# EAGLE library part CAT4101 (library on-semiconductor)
1A Constant-Current LED Driver with PWM Dimming Source: ON Semiconductor .. 4101.pdf

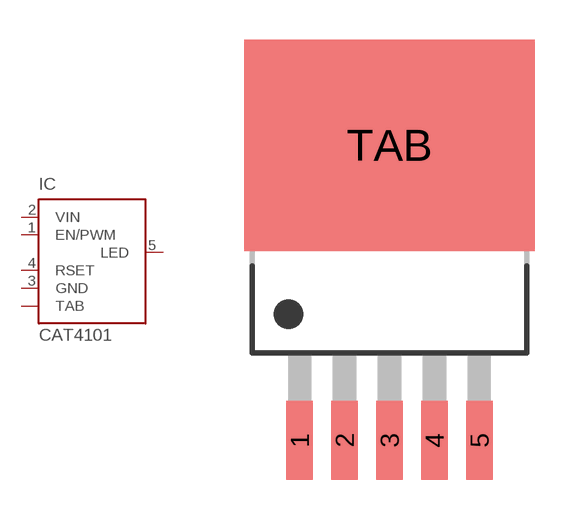
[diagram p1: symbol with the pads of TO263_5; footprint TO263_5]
Designator prefix IC

## CAT4101 (MPN: CAT4101TV-T75; OC_FARNELL: 1718452; OC_NEWARK: 08R5264)  [TO263_5]
1  EN/PWM  in
2  VIN  in
3  GND  pwr
4  RSET  in
5  LED  pwr
TAB  TAB  pas

## Footprint TO263_5 (pad centres in mm)
TO-263 5-LEAD (TV) Source: ON Semiconductor .. 4101.pdf
smd 1 x 3: 1 -3.4,-8; 2 -1.7,-8; 3 0,-8; 4 1.7,-8; 5 3.4,-8
smd 11 x 8: TAB 0,3.175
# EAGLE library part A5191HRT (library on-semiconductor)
HART Modem Single-chip, half-duplex 1200 bits per second FSK modem Auto generated by make-symbol-device-package-bsdl.ulp Rev. 35 Source:OnSemi A5191HRT HART Modem Data Sheet.pdf

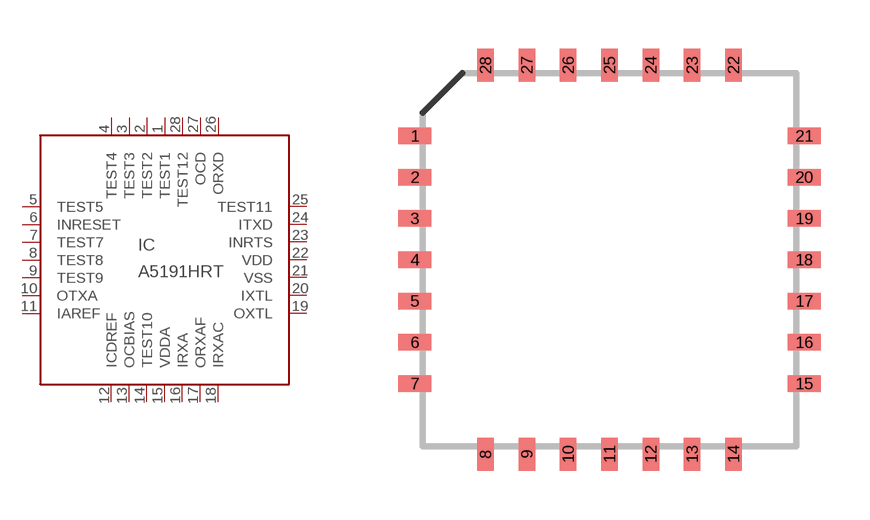
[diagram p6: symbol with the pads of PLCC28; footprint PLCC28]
Designator prefix IC

## A5191HRT (MPN: A5191HRTPG-XTD; OC_FARNELL: unknown; OC_NEWARK: 03P1167)  [PLCC28]
1  TEST1  in
2  TEST2  nc
3  TEST3  nc
4  TEST4  nc
5  TEST5  in
6  INRESET  in
7  TEST7  in
8  TEST8  in
9  TEST9  in
10  OTXA  out
11  IAREF  in
12  ICDREF  in
13  OCBIAS  out
14  TEST10  in
15  VDDA  pwr
16  IRXA  in
17  ORXAF  out
18  IRXAC  in
19  OXTL  out
20  IXTL  in
21  VSS  pwr
22  VDD  pwr
23  INRTS  in
24  ITXD  in
25  TEST11  nc
26  ORXD  out
27  OCD  out
28  TEST12  nc

## Footprint PLCC28 (pad centres in mm)
Auto generated by make-symbol-device-package-bsdl.ulp Rev. 35
smd 1.016 x 0.508: 1 -5.982,3.81; 2 -5.982,2.54; 3 -5.982,1.27; 4 -5.982,0; 5 -5.982,-1.27; 6 -5.982,-2.54; 7 -5.982,-3.81; 15 5.982,-3.81; 16 5.982,-2.54; 17 5.982,-1.27; 18 5.982,0; 19 5.982,1.27; 20 5.982,2.54; 21 5.982,3.81
smd 0.508 x 1.016: 8 -3.81,-5.982; 9 -2.54,-5.982; 10 -1.27,-5.982; 11 0,-5.982; 12 1.27,-5.982; 13 2.54,-5.982; 14 3.81,-5.982; 22 3.81,5.982; 23 2.54,5.982; 24 1.27,5.982; 25 0,5.982; 26 -1.27,5.982; 27 -2.54,5.982; 28 -3.81,5.982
